VERSION 5.7 ;
BUSBITCHARS "[]" ;
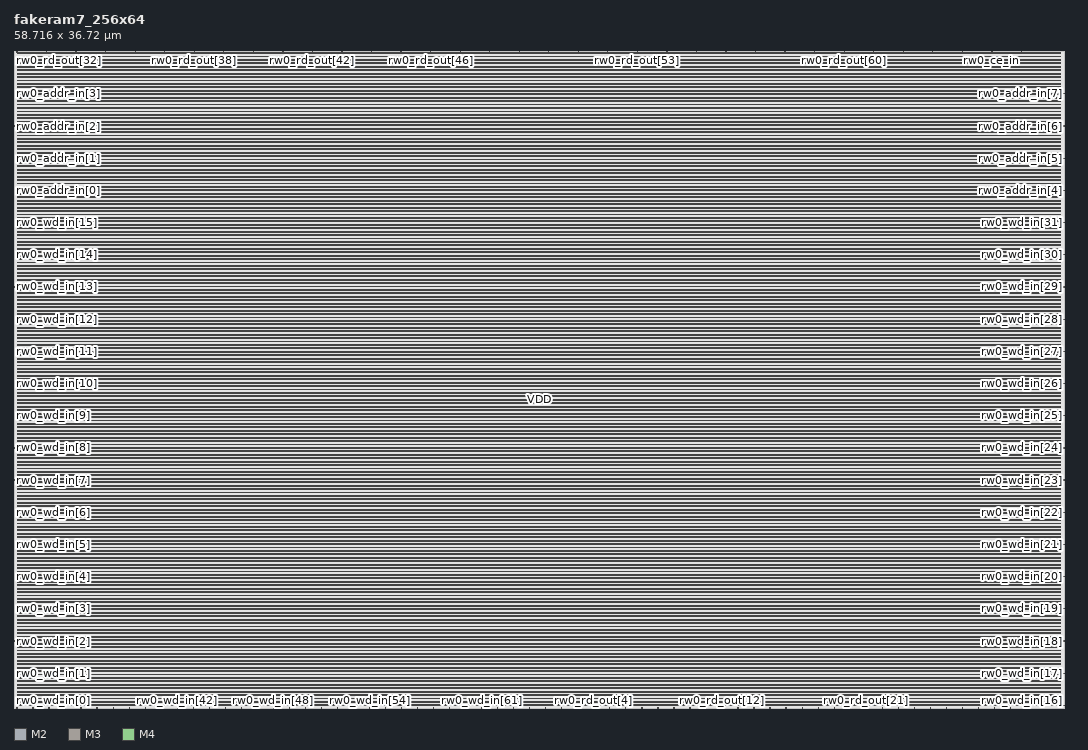
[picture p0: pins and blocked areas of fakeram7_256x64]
MACRO fakeram7_256x64
  FOREIGN fakeram7_256x64 0 0 ;
  SYMMETRY X Y R90 ;
  SIZE 58.716 BY 36.720 ;
  CLASS BLOCK ;
  PIN rw0_wd_in[0]
    DIRECTION INPUT ;
    USE SIGNAL ;
    SHAPE ABUTMENT ;
    PORT
      LAYER M2 ;
      RECT 0.000 0.138 0.036 0.150 ;
    END
  END rw0_wd_in[0]
  PIN rw0_wd_in[1]
    DIRECTION INPUT ;
    USE SIGNAL ;
    SHAPE ABUTMENT ;
    PORT
      LAYER M2 ;
      RECT 0.000 1.938 0.036 1.950 ;
    END
  END rw0_wd_in[1]
  PIN rw0_wd_in[2]
    DIRECTION INPUT ;
    USE SIGNAL ;
    SHAPE ABUTMENT ;
    PORT
      LAYER M2 ;
      RECT 0.000 3.738 0.036 3.750 ;
    END
  END rw0_wd_in[2]
  PIN rw0_wd_in[3]
    DIRECTION INPUT ;
    USE SIGNAL ;
    SHAPE ABUTMENT ;
    PORT
      LAYER M2 ;
      RECT 0.000 5.538 0.036 5.550 ;
    END
  END rw0_wd_in[3]
  PIN rw0_wd_in[4]
    DIRECTION INPUT ;
    USE SIGNAL ;
    SHAPE ABUTMENT ;
    PORT
      LAYER M2 ;
      RECT 0.000 7.338 0.036 7.350 ;
    END
  END rw0_wd_in[4]
  PIN rw0_wd_in[5]
    DIRECTION INPUT ;
    USE SIGNAL ;
    SHAPE ABUTMENT ;
    PORT
      LAYER M2 ;
      RECT 0.000 9.138 0.036 9.150 ;
    END
  END rw0_wd_in[5]
  PIN rw0_wd_in[6]
    DIRECTION INPUT ;
    USE SIGNAL ;
    SHAPE ABUTMENT ;
    PORT
      LAYER M2 ;
      RECT 0.000 10.938 0.036 10.950 ;
    END
  END rw0_wd_in[6]
  PIN rw0_wd_in[7]
    DIRECTION INPUT ;
    USE SIGNAL ;
    SHAPE ABUTMENT ;
    PORT
      LAYER M2 ;
      RECT 0.000 12.738 0.036 12.750 ;
    END
  END rw0_wd_in[7]
  PIN rw0_wd_in[8]
    DIRECTION INPUT ;
    USE SIGNAL ;
    SHAPE ABUTMENT ;
    PORT
      LAYER M2 ;
      RECT 0.000 14.538 0.036 14.550 ;
    END
  END rw0_wd_in[8]
  PIN rw0_wd_in[9]
    DIRECTION INPUT ;
    USE SIGNAL ;
    SHAPE ABUTMENT ;
    PORT
      LAYER M2 ;
      RECT 0.000 16.338 0.036 16.350 ;
    END
  END rw0_wd_in[9]
  PIN rw0_wd_in[10]
    DIRECTION INPUT ;
    USE SIGNAL ;
    SHAPE ABUTMENT ;
    PORT
      LAYER M2 ;
      RECT 0.000 18.138 0.036 18.150 ;
    END
  END rw0_wd_in[10]
  PIN rw0_wd_in[11]
    DIRECTION INPUT ;
    USE SIGNAL ;
    SHAPE ABUTMENT ;
    PORT
      LAYER M2 ;
      RECT 0.000 19.938 0.036 19.950 ;
    END
  END rw0_wd_in[11]
  PIN rw0_wd_in[12]
    DIRECTION INPUT ;
    USE SIGNAL ;
    SHAPE ABUTMENT ;
    PORT
      LAYER M2 ;
      RECT 0.000 21.738 0.036 21.750 ;
    END
  END rw0_wd_in[12]
  PIN rw0_wd_in[13]
    DIRECTION INPUT ;
    USE SIGNAL ;
    SHAPE ABUTMENT ;
    PORT
      LAYER M2 ;
      RECT 0.000 23.538 0.036 23.550 ;
    END
  END rw0_wd_in[13]
  PIN rw0_wd_in[14]
    DIRECTION INPUT ;
    USE SIGNAL ;
    SHAPE ABUTMENT ;
    PORT
      LAYER M2 ;
      RECT 0.000 25.338 0.036 25.350 ;
    END
  END rw0_wd_in[14]
  PIN rw0_wd_in[15]
    DIRECTION INPUT ;
    USE SIGNAL ;
    SHAPE ABUTMENT ;
    PORT
      LAYER M2 ;
      RECT 0.000 27.138 0.036 27.150 ;
    END
  END rw0_wd_in[15]
  PIN rw0_wd_in[16]
    DIRECTION INPUT ;
    USE SIGNAL ;
    SHAPE ABUTMENT ;
    PORT
      LAYER M2 ;
      RECT 58.680 0.138 58.716 0.150 ;
    END
  END rw0_wd_in[16]
  PIN rw0_wd_in[17]
    DIRECTION INPUT ;
    USE SIGNAL ;
    SHAPE ABUTMENT ;
    PORT
      LAYER M2 ;
      RECT 58.680 1.938 58.716 1.950 ;
    END
  END rw0_wd_in[17]
  PIN rw0_wd_in[18]
    DIRECTION INPUT ;
    USE SIGNAL ;
    SHAPE ABUTMENT ;
    PORT
      LAYER M2 ;
      RECT 58.680 3.738 58.716 3.750 ;
    END
  END rw0_wd_in[18]
  PIN rw0_wd_in[19]
    DIRECTION INPUT ;
    USE SIGNAL ;
    SHAPE ABUTMENT ;
    PORT
      LAYER M2 ;
      RECT 58.680 5.538 58.716 5.550 ;
    END
  END rw0_wd_in[19]
  PIN rw0_wd_in[20]
    DIRECTION INPUT ;
    USE SIGNAL ;
    SHAPE ABUTMENT ;
    PORT
      LAYER M2 ;
      RECT 58.680 7.338 58.716 7.350 ;
    END
  END rw0_wd_in[20]
  PIN rw0_wd_in[21]
    DIRECTION INPUT ;
    USE SIGNAL ;
    SHAPE ABUTMENT ;
    PORT
      LAYER M2 ;
      RECT 58.680 9.138 58.716 9.150 ;
    END
  END rw0_wd_in[21]
  PIN rw0_wd_in[22]
    DIRECTION INPUT ;
    USE SIGNAL ;
    SHAPE ABUTMENT ;
    PORT
      LAYER M2 ;
      RECT 58.680 10.938 58.716 10.950 ;
    END
  END rw0_wd_in[22]
  PIN rw0_wd_in[23]
    DIRECTION INPUT ;
    USE SIGNAL ;
    SHAPE ABUTMENT ;
    PORT
      LAYER M2 ;
      RECT 58.680 12.738 58.716 12.750 ;
    END
  END rw0_wd_in[23]
  PIN rw0_wd_in[24]
    DIRECTION INPUT ;
    USE SIGNAL ;
    SHAPE ABUTMENT ;
    PORT
      LAYER M2 ;
      RECT 58.680 14.538 58.716 14.550 ;
    END
  END rw0_wd_in[24]
  PIN rw0_wd_in[25]
    DIRECTION INPUT ;
    USE SIGNAL ;
    SHAPE ABUTMENT ;
    PORT
      LAYER M2 ;
      RECT 58.680 16.338 58.716 16.350 ;
    END
  END rw0_wd_in[25]
  PIN rw0_wd_in[26]
    DIRECTION INPUT ;
    USE SIGNAL ;
    SHAPE ABUTMENT ;
    PORT
      LAYER M2 ;
      RECT 58.680 18.138 58.716 18.150 ;
    END
  END rw0_wd_in[26]
  PIN rw0_wd_in[27]
    DIRECTION INPUT ;
    USE SIGNAL ;
    SHAPE ABUTMENT ;
    PORT
      LAYER M2 ;
      RECT 58.680 19.938 58.716 19.950 ;
    END
  END rw0_wd_in[27]
  PIN rw0_wd_in[28]
    DIRECTION INPUT ;
    USE SIGNAL ;
    SHAPE ABUTMENT ;
    PORT
      LAYER M2 ;
      RECT 58.680 21.738 58.716 21.750 ;
    END
  END rw0_wd_in[28]
  PIN rw0_wd_in[29]
    DIRECTION INPUT ;
    USE SIGNAL ;
    SHAPE ABUTMENT ;
    PORT
      LAYER M2 ;
      RECT 58.680 23.538 58.716 23.550 ;
    END
  END rw0_wd_in[29]
  PIN rw0_wd_in[30]
    DIRECTION INPUT ;
    USE SIGNAL ;
    SHAPE ABUTMENT ;
    PORT
      LAYER M2 ;
      RECT 58.680 25.338 58.716 25.350 ;
    END
  END rw0_wd_in[30]
  PIN rw0_wd_in[31]
    DIRECTION INPUT ;
    USE SIGNAL ;
    SHAPE ABUTMENT ;
    PORT
      LAYER M2 ;
      RECT 58.680 27.138 58.716 27.150 ;
    END
  END rw0_wd_in[31]
  PIN rw0_wd_in[32]
    DIRECTION INPUT ;
    USE SIGNAL ;
    SHAPE ABUTMENT ;
    PORT
      LAYER M3 ;
      RECT 0.161 0.000 0.175 0.042 ;
    END
  END rw0_wd_in[32]
  PIN rw0_wd_in[33]
    DIRECTION INPUT ;
    USE SIGNAL ;
    SHAPE ABUTMENT ;
    PORT
      LAYER M3 ;
      RECT 1.057 0.000 1.071 0.042 ;
    END
  END rw0_wd_in[33]
  PIN rw0_wd_in[34]
    DIRECTION INPUT ;
    USE SIGNAL ;
    SHAPE ABUTMENT ;
    PORT
      LAYER M3 ;
      RECT 1.953 0.000 1.967 0.042 ;
    END
  END rw0_wd_in[34]
  PIN rw0_wd_in[35]
    DIRECTION INPUT ;
    USE SIGNAL ;
    SHAPE ABUTMENT ;
    PORT
      LAYER M3 ;
      RECT 2.849 0.000 2.863 0.042 ;
    END
  END rw0_wd_in[35]
  PIN rw0_wd_in[36]
    DIRECTION INPUT ;
    USE SIGNAL ;
    SHAPE ABUTMENT ;
    PORT
      LAYER M3 ;
      RECT 3.745 0.000 3.759 0.042 ;
    END
  END rw0_wd_in[36]
  PIN rw0_wd_in[37]
    DIRECTION INPUT ;
    USE SIGNAL ;
    SHAPE ABUTMENT ;
    PORT
      LAYER M3 ;
      RECT 4.641 0.000 4.655 0.042 ;
    END
  END rw0_wd_in[37]
  PIN rw0_wd_in[38]
    DIRECTION INPUT ;
    USE SIGNAL ;
    SHAPE ABUTMENT ;
    PORT
      LAYER M3 ;
      RECT 5.537 0.000 5.551 0.042 ;
    END
  END rw0_wd_in[38]
  PIN rw0_wd_in[39]
    DIRECTION INPUT ;
    USE SIGNAL ;
    SHAPE ABUTMENT ;
    PORT
      LAYER M3 ;
      RECT 6.433 0.000 6.447 0.042 ;
    END
  END rw0_wd_in[39]
  PIN rw0_wd_in[40]
    DIRECTION INPUT ;
    USE SIGNAL ;
    SHAPE ABUTMENT ;
    PORT
      LAYER M3 ;
      RECT 7.329 0.000 7.343 0.042 ;
    END
  END rw0_wd_in[40]
  PIN rw0_wd_in[41]
    DIRECTION INPUT ;
    USE SIGNAL ;
    SHAPE ABUTMENT ;
    PORT
      LAYER M3 ;
      RECT 8.225 0.000 8.239 0.042 ;
    END
  END rw0_wd_in[41]
  PIN rw0_wd_in[42]
    DIRECTION INPUT ;
    USE SIGNAL ;
    SHAPE ABUTMENT ;
    PORT
      LAYER M3 ;
      RECT 9.121 0.000 9.135 0.042 ;
    END
  END rw0_wd_in[42]
  PIN rw0_wd_in[43]
    DIRECTION INPUT ;
    USE SIGNAL ;
    SHAPE ABUTMENT ;
    PORT
      LAYER M3 ;
      RECT 10.017 0.000 10.031 0.042 ;
    END
  END rw0_wd_in[43]
  PIN rw0_wd_in[44]
    DIRECTION INPUT ;
    USE SIGNAL ;
    SHAPE ABUTMENT ;
    PORT
      LAYER M3 ;
      RECT 10.913 0.000 10.927 0.042 ;
    END
  END rw0_wd_in[44]
  PIN rw0_wd_in[45]
    DIRECTION INPUT ;
    USE SIGNAL ;
    SHAPE ABUTMENT ;
    PORT
      LAYER M3 ;
      RECT 11.809 0.000 11.823 0.042 ;
    END
  END rw0_wd_in[45]
  PIN rw0_wd_in[46]
    DIRECTION INPUT ;
    USE SIGNAL ;
    SHAPE ABUTMENT ;
    PORT
      LAYER M3 ;
      RECT 12.705 0.000 12.719 0.042 ;
    END
  END rw0_wd_in[46]
  PIN rw0_wd_in[47]
    DIRECTION INPUT ;
    USE SIGNAL ;
    SHAPE ABUTMENT ;
    PORT
      LAYER M3 ;
      RECT 13.601 0.000 13.615 0.042 ;
    END
  END rw0_wd_in[47]
  PIN rw0_wd_in[48]
    DIRECTION INPUT ;
    USE SIGNAL ;
    SHAPE ABUTMENT ;
    PORT
      LAYER M3 ;
      RECT 14.497 0.000 14.511 0.042 ;
    END
  END rw0_wd_in[48]
  PIN rw0_wd_in[49]
    DIRECTION INPUT ;
    USE SIGNAL ;
    SHAPE ABUTMENT ;
    PORT
      LAYER M3 ;
      RECT 15.393 0.000 15.407 0.042 ;
    END
  END rw0_wd_in[49]
  PIN rw0_wd_in[50]
    DIRECTION INPUT ;
    USE SIGNAL ;
    SHAPE ABUTMENT ;
    PORT
      LAYER M3 ;
      RECT 16.289 0.000 16.303 0.042 ;
    END
  END rw0_wd_in[50]
  PIN rw0_wd_in[51]
    DIRECTION INPUT ;
    USE SIGNAL ;
    SHAPE ABUTMENT ;
    PORT
      LAYER M3 ;
      RECT 17.185 0.000 17.199 0.042 ;
    END
  END rw0_wd_in[51]
  PIN rw0_wd_in[52]
    DIRECTION INPUT ;
    USE SIGNAL ;
    SHAPE ABUTMENT ;
    PORT
      LAYER M3 ;
      RECT 18.081 0.000 18.095 0.042 ;
    END
  END rw0_wd_in[52]
  PIN rw0_wd_in[53]
    DIRECTION INPUT ;
    USE SIGNAL ;
    SHAPE ABUTMENT ;
    PORT
      LAYER M3 ;
      RECT 18.977 0.000 18.991 0.042 ;
    END
  END rw0_wd_in[53]
  PIN rw0_wd_in[54]
    DIRECTION INPUT ;
    USE SIGNAL ;
    SHAPE ABUTMENT ;
    PORT
      LAYER M3 ;
      RECT 19.873 0.000 19.887 0.042 ;
    END
  END rw0_wd_in[54]
  PIN rw0_wd_in[55]
    DIRECTION INPUT ;
    USE SIGNAL ;
    SHAPE ABUTMENT ;
    PORT
      LAYER M3 ;
      RECT 20.769 0.000 20.783 0.042 ;
    END
  END rw0_wd_in[55]
  PIN rw0_wd_in[56]
    DIRECTION INPUT ;
    USE SIGNAL ;
    SHAPE ABUTMENT ;
    PORT
      LAYER M3 ;
      RECT 21.665 0.000 21.679 0.042 ;
    END
  END rw0_wd_in[56]
  PIN rw0_wd_in[57]
    DIRECTION INPUT ;
    USE SIGNAL ;
    SHAPE ABUTMENT ;
    PORT
      LAYER M3 ;
      RECT 22.561 0.000 22.575 0.042 ;
    END
  END rw0_wd_in[57]
  PIN rw0_wd_in[58]
    DIRECTION INPUT ;
    USE SIGNAL ;
    SHAPE ABUTMENT ;
    PORT
      LAYER M3 ;
      RECT 23.457 0.000 23.471 0.042 ;
    END
  END rw0_wd_in[58]
  PIN rw0_wd_in[59]
    DIRECTION INPUT ;
    USE SIGNAL ;
    SHAPE ABUTMENT ;
    PORT
      LAYER M3 ;
      RECT 24.353 0.000 24.367 0.042 ;
    END
  END rw0_wd_in[59]
  PIN rw0_wd_in[60]
    DIRECTION INPUT ;
    USE SIGNAL ;
    SHAPE ABUTMENT ;
    PORT
      LAYER M3 ;
      RECT 25.249 0.000 25.263 0.042 ;
    END
  END rw0_wd_in[60]
  PIN rw0_wd_in[61]
    DIRECTION INPUT ;
    USE SIGNAL ;
    SHAPE ABUTMENT ;
    PORT
      LAYER M3 ;
      RECT 26.145 0.000 26.159 0.042 ;
    END
  END rw0_wd_in[61]
  PIN rw0_wd_in[62]
    DIRECTION INPUT ;
    USE SIGNAL ;
    SHAPE ABUTMENT ;
    PORT
      LAYER M3 ;
      RECT 27.041 0.000 27.055 0.042 ;
    END
  END rw0_wd_in[62]
  PIN rw0_wd_in[63]
    DIRECTION INPUT ;
    USE SIGNAL ;
    SHAPE ABUTMENT ;
    PORT
      LAYER M3 ;
      RECT 27.937 0.000 27.951 0.042 ;
    END
  END rw0_wd_in[63]
  PIN rw0_rd_out[0]
    DIRECTION OUTPUT ;
    USE SIGNAL ;
    SHAPE ABUTMENT ;
    PORT
      LAYER M3 ;
      RECT 28.833 0.000 28.847 0.042 ;
    END
  END rw0_rd_out[0]
  PIN rw0_rd_out[1]
    DIRECTION OUTPUT ;
    USE SIGNAL ;
    SHAPE ABUTMENT ;
    PORT
      LAYER M3 ;
      RECT 29.729 0.000 29.743 0.042 ;
    END
  END rw0_rd_out[1]
  PIN rw0_rd_out[2]
    DIRECTION OUTPUT ;
    USE SIGNAL ;
    SHAPE ABUTMENT ;
    PORT
      LAYER M3 ;
      RECT 30.625 0.000 30.639 0.042 ;
    END
  END rw0_rd_out[2]
  PIN rw0_rd_out[3]
    DIRECTION OUTPUT ;
    USE SIGNAL ;
    SHAPE ABUTMENT ;
    PORT
      LAYER M3 ;
      RECT 31.521 0.000 31.535 0.042 ;
    END
  END rw0_rd_out[3]
  PIN rw0_rd_out[4]
    DIRECTION OUTPUT ;
    USE SIGNAL ;
    SHAPE ABUTMENT ;
    PORT
      LAYER M3 ;
      RECT 32.417 0.000 32.431 0.042 ;
    END
  END rw0_rd_out[4]
  PIN rw0_rd_out[5]
    DIRECTION OUTPUT ;
    USE SIGNAL ;
    SHAPE ABUTMENT ;
    PORT
      LAYER M3 ;
      RECT 33.313 0.000 33.327 0.042 ;
    END
  END rw0_rd_out[5]
  PIN rw0_rd_out[6]
    DIRECTION OUTPUT ;
    USE SIGNAL ;
    SHAPE ABUTMENT ;
    PORT
      LAYER M3 ;
      RECT 34.209 0.000 34.223 0.042 ;
    END
  END rw0_rd_out[6]
  PIN rw0_rd_out[7]
    DIRECTION OUTPUT ;
    USE SIGNAL ;
    SHAPE ABUTMENT ;
    PORT
      LAYER M3 ;
      RECT 35.105 0.000 35.119 0.042 ;
    END
  END rw0_rd_out[7]
  PIN rw0_rd_out[8]
    DIRECTION OUTPUT ;
    USE SIGNAL ;
    SHAPE ABUTMENT ;
    PORT
      LAYER M3 ;
      RECT 36.001 0.000 36.015 0.042 ;
    END
  END rw0_rd_out[8]
  PIN rw0_rd_out[9]
    DIRECTION OUTPUT ;
    USE SIGNAL ;
    SHAPE ABUTMENT ;
    PORT
      LAYER M3 ;
      RECT 36.897 0.000 36.911 0.042 ;
    END
  END rw0_rd_out[9]
  PIN rw0_rd_out[10]
    DIRECTION OUTPUT ;
    USE SIGNAL ;
    SHAPE ABUTMENT ;
    PORT
      LAYER M3 ;
      RECT 37.793 0.000 37.807 0.042 ;
    END
  END rw0_rd_out[10]
  PIN rw0_rd_out[11]
    DIRECTION OUTPUT ;
    USE SIGNAL ;
    SHAPE ABUTMENT ;
    PORT
      LAYER M3 ;
      RECT 38.689 0.000 38.703 0.042 ;
    END
  END rw0_rd_out[11]
  PIN rw0_rd_out[12]
    DIRECTION OUTPUT ;
    USE SIGNAL ;
    SHAPE ABUTMENT ;
    PORT
      LAYER M3 ;
      RECT 39.585 0.000 39.599 0.042 ;
    END
  END rw0_rd_out[12]
  PIN rw0_rd_out[13]
    DIRECTION OUTPUT ;
    USE SIGNAL ;
    SHAPE ABUTMENT ;
    PORT
      LAYER M3 ;
      RECT 40.481 0.000 40.495 0.042 ;
    END
  END rw0_rd_out[13]
  PIN rw0_rd_out[14]
    DIRECTION OUTPUT ;
    USE SIGNAL ;
    SHAPE ABUTMENT ;
    PORT
      LAYER M3 ;
      RECT 41.377 0.000 41.391 0.042 ;
    END
  END rw0_rd_out[14]
  PIN rw0_rd_out[15]
    DIRECTION OUTPUT ;
    USE SIGNAL ;
    SHAPE ABUTMENT ;
    PORT
      LAYER M3 ;
      RECT 42.273 0.000 42.287 0.042 ;
    END
  END rw0_rd_out[15]
  PIN rw0_rd_out[16]
    DIRECTION OUTPUT ;
    USE SIGNAL ;
    SHAPE ABUTMENT ;
    PORT
      LAYER M3 ;
      RECT 43.169 0.000 43.183 0.042 ;
    END
  END rw0_rd_out[16]
  PIN rw0_rd_out[17]
    DIRECTION OUTPUT ;
    USE SIGNAL ;
    SHAPE ABUTMENT ;
    PORT
      LAYER M3 ;
      RECT 44.065 0.000 44.079 0.042 ;
    END
  END rw0_rd_out[17]
  PIN rw0_rd_out[18]
    DIRECTION OUTPUT ;
    USE SIGNAL ;
    SHAPE ABUTMENT ;
    PORT
      LAYER M3 ;
      RECT 44.961 0.000 44.975 0.042 ;
    END
  END rw0_rd_out[18]
  PIN rw0_rd_out[19]
    DIRECTION OUTPUT ;
    USE SIGNAL ;
    SHAPE ABUTMENT ;
    PORT
      LAYER M3 ;
      RECT 45.857 0.000 45.871 0.042 ;
    END
  END rw0_rd_out[19]
  PIN rw0_rd_out[20]
    DIRECTION OUTPUT ;
    USE SIGNAL ;
    SHAPE ABUTMENT ;
    PORT
      LAYER M3 ;
      RECT 46.753 0.000 46.767 0.042 ;
    END
  END rw0_rd_out[20]
  PIN rw0_rd_out[21]
    DIRECTION OUTPUT ;
    USE SIGNAL ;
    SHAPE ABUTMENT ;
    PORT
      LAYER M3 ;
      RECT 47.649 0.000 47.663 0.042 ;
    END
  END rw0_rd_out[21]
  PIN rw0_rd_out[22]
    DIRECTION OUTPUT ;
    USE SIGNAL ;
    SHAPE ABUTMENT ;
    PORT
      LAYER M3 ;
      RECT 48.545 0.000 48.559 0.042 ;
    END
  END rw0_rd_out[22]
  PIN rw0_rd_out[23]
    DIRECTION OUTPUT ;
    USE SIGNAL ;
    SHAPE ABUTMENT ;
    PORT
      LAYER M3 ;
      RECT 49.441 0.000 49.455 0.042 ;
    END
  END rw0_rd_out[23]
  PIN rw0_rd_out[24]
    DIRECTION OUTPUT ;
    USE SIGNAL ;
    SHAPE ABUTMENT ;
    PORT
      LAYER M3 ;
      RECT 50.337 0.000 50.351 0.042 ;
    END
  END rw0_rd_out[24]
  PIN rw0_rd_out[25]
    DIRECTION OUTPUT ;
    USE SIGNAL ;
    SHAPE ABUTMENT ;
    PORT
      LAYER M3 ;
      RECT 51.233 0.000 51.247 0.042 ;
    END
  END rw0_rd_out[25]
  PIN rw0_rd_out[26]
    DIRECTION OUTPUT ;
    USE SIGNAL ;
    SHAPE ABUTMENT ;
    PORT
      LAYER M3 ;
      RECT 52.129 0.000 52.143 0.042 ;
    END
  END rw0_rd_out[26]
  PIN rw0_rd_out[27]
    DIRECTION OUTPUT ;
    USE SIGNAL ;
    SHAPE ABUTMENT ;
    PORT
      LAYER M3 ;
      RECT 53.025 0.000 53.039 0.042 ;
    END
  END rw0_rd_out[27]
  PIN rw0_rd_out[28]
    DIRECTION OUTPUT ;
    USE SIGNAL ;
    SHAPE ABUTMENT ;
    PORT
      LAYER M3 ;
      RECT 53.921 0.000 53.935 0.042 ;
    END
  END rw0_rd_out[28]
  PIN rw0_rd_out[29]
    DIRECTION OUTPUT ;
    USE SIGNAL ;
    SHAPE ABUTMENT ;
    PORT
      LAYER M3 ;
      RECT 54.817 0.000 54.831 0.042 ;
    END
  END rw0_rd_out[29]
  PIN rw0_rd_out[30]
    DIRECTION OUTPUT ;
    USE SIGNAL ;
    SHAPE ABUTMENT ;
    PORT
      LAYER M3 ;
      RECT 55.713 0.000 55.727 0.042 ;
    END
  END rw0_rd_out[30]
  PIN rw0_rd_out[31]
    DIRECTION OUTPUT ;
    USE SIGNAL ;
    SHAPE ABUTMENT ;
    PORT
      LAYER M3 ;
      RECT 56.609 0.000 56.623 0.042 ;
    END
  END rw0_rd_out[31]
  PIN rw0_rd_out[32]
    DIRECTION OUTPUT ;
    USE SIGNAL ;
    SHAPE ABUTMENT ;
    PORT
      LAYER M3 ;
      RECT 0.161 36.678 0.175 36.720 ;
    END
  END rw0_rd_out[32]
  PIN rw0_rd_out[33]
    DIRECTION OUTPUT ;
    USE SIGNAL ;
    SHAPE ABUTMENT ;
    PORT
      LAYER M3 ;
      RECT 1.813 36.678 1.827 36.720 ;
    END
  END rw0_rd_out[33]
  PIN rw0_rd_out[34]
    DIRECTION OUTPUT ;
    USE SIGNAL ;
    SHAPE ABUTMENT ;
    PORT
      LAYER M3 ;
      RECT 3.465 36.678 3.479 36.720 ;
    END
  END rw0_rd_out[34]
  PIN rw0_rd_out[35]
    DIRECTION OUTPUT ;
    USE SIGNAL ;
    SHAPE ABUTMENT ;
    PORT
      LAYER M3 ;
      RECT 5.117 36.678 5.131 36.720 ;
    END
  END rw0_rd_out[35]
  PIN rw0_rd_out[36]
    DIRECTION OUTPUT ;
    USE SIGNAL ;
    SHAPE ABUTMENT ;
    PORT
      LAYER M3 ;
      RECT 6.769 36.678 6.783 36.720 ;
    END
  END rw0_rd_out[36]
  PIN rw0_rd_out[37]
    DIRECTION OUTPUT ;
    USE SIGNAL ;
    SHAPE ABUTMENT ;
    PORT
      LAYER M3 ;
      RECT 8.421 36.678 8.435 36.720 ;
    END
  END rw0_rd_out[37]
  PIN rw0_rd_out[38]
    DIRECTION OUTPUT ;
    USE SIGNAL ;
    SHAPE ABUTMENT ;
    PORT
      LAYER M3 ;
      RECT 10.073 36.678 10.087 36.720 ;
    END
  END rw0_rd_out[38]
  PIN rw0_rd_out[39]
    DIRECTION OUTPUT ;
    USE SIGNAL ;
    SHAPE ABUTMENT ;
    PORT
      LAYER M3 ;
      RECT 11.725 36.678 11.739 36.720 ;
    END
  END rw0_rd_out[39]
  PIN rw0_rd_out[40]
    DIRECTION OUTPUT ;
    USE SIGNAL ;
    SHAPE ABUTMENT ;
    PORT
      LAYER M3 ;
      RECT 13.377 36.678 13.391 36.720 ;
    END
  END rw0_rd_out[40]
  PIN rw0_rd_out[41]
    DIRECTION OUTPUT ;
    USE SIGNAL ;
    SHAPE ABUTMENT ;
    PORT
      LAYER M3 ;
      RECT 15.029 36.678 15.043 36.720 ;
    END
  END rw0_rd_out[41]
  PIN rw0_rd_out[42]
    DIRECTION OUTPUT ;
    USE SIGNAL ;
    SHAPE ABUTMENT ;
    PORT
      LAYER M3 ;
      RECT 16.681 36.678 16.695 36.720 ;
    END
  END rw0_rd_out[42]
  PIN rw0_rd_out[43]
    DIRECTION OUTPUT ;
    USE SIGNAL ;
    SHAPE ABUTMENT ;
    PORT
      LAYER M3 ;
      RECT 18.333 36.678 18.347 36.720 ;
    END
  END rw0_rd_out[43]
  PIN rw0_rd_out[44]
    DIRECTION OUTPUT ;
    USE SIGNAL ;
    SHAPE ABUTMENT ;
    PORT
      LAYER M3 ;
      RECT 19.985 36.678 19.999 36.720 ;
    END
  END rw0_rd_out[44]
  PIN rw0_rd_out[45]
    DIRECTION OUTPUT ;
    USE SIGNAL ;
    SHAPE ABUTMENT ;
    PORT
      LAYER M3 ;
      RECT 21.637 36.678 21.651 36.720 ;
    END
  END rw0_rd_out[45]
  PIN rw0_rd_out[46]
    DIRECTION OUTPUT ;
    USE SIGNAL ;
    SHAPE ABUTMENT ;
    PORT
      LAYER M3 ;
      RECT 23.289 36.678 23.303 36.720 ;
    END
  END rw0_rd_out[46]
  PIN rw0_rd_out[47]
    DIRECTION OUTPUT ;
    USE SIGNAL ;
    SHAPE ABUTMENT ;
    PORT
      LAYER M3 ;
      RECT 24.941 36.678 24.955 36.720 ;
    END
  END rw0_rd_out[47]
  PIN rw0_rd_out[48]
    DIRECTION OUTPUT ;
    USE SIGNAL ;
    SHAPE ABUTMENT ;
    PORT
      LAYER M3 ;
      RECT 26.593 36.678 26.607 36.720 ;
    END
  END rw0_rd_out[48]
  PIN rw0_rd_out[49]
    DIRECTION OUTPUT ;
    USE SIGNAL ;
    SHAPE ABUTMENT ;
    PORT
      LAYER M3 ;
      RECT 28.245 36.678 28.259 36.720 ;
    END
  END rw0_rd_out[49]
  PIN rw0_rd_out[50]
    DIRECTION OUTPUT ;
    USE SIGNAL ;
    SHAPE ABUTMENT ;
    PORT
      LAYER M3 ;
      RECT 29.897 36.678 29.911 36.720 ;
    END
  END rw0_rd_out[50]
  PIN rw0_rd_out[51]
    DIRECTION OUTPUT ;
    USE SIGNAL ;
    SHAPE ABUTMENT ;
    PORT
      LAYER M3 ;
      RECT 31.549 36.678 31.563 36.720 ;
    END
  END rw0_rd_out[51]
  PIN rw0_rd_out[52]
    DIRECTION OUTPUT ;
    USE SIGNAL ;
    SHAPE ABUTMENT ;
    PORT
      LAYER M3 ;
      RECT 33.201 36.678 33.215 36.720 ;
    END
  END rw0_rd_out[52]
  PIN rw0_rd_out[53]
    DIRECTION OUTPUT ;
    USE SIGNAL ;
    SHAPE ABUTMENT ;
    PORT
      LAYER M3 ;
      RECT 34.853 36.678 34.867 36.720 ;
    END
  END rw0_rd_out[53]
  PIN rw0_rd_out[54]
    DIRECTION OUTPUT ;
    USE SIGNAL ;
    SHAPE ABUTMENT ;
    PORT
      LAYER M3 ;
      RECT 36.505 36.678 36.519 36.720 ;
    END
  END rw0_rd_out[54]
  PIN rw0_rd_out[55]
    DIRECTION OUTPUT ;
    USE SIGNAL ;
    SHAPE ABUTMENT ;
    PORT
      LAYER M3 ;
      RECT 38.157 36.678 38.171 36.720 ;
    END
  END rw0_rd_out[55]
  PIN rw0_rd_out[56]
    DIRECTION OUTPUT ;
    USE SIGNAL ;
    SHAPE ABUTMENT ;
    PORT
      LAYER M3 ;
      RECT 39.809 36.678 39.823 36.720 ;
    END
  END rw0_rd_out[56]
  PIN rw0_rd_out[57]
    DIRECTION OUTPUT ;
    USE SIGNAL ;
    SHAPE ABUTMENT ;
    PORT
      LAYER M3 ;
      RECT 41.461 36.678 41.475 36.720 ;
    END
  END rw0_rd_out[57]
  PIN rw0_rd_out[58]
    DIRECTION OUTPUT ;
    USE SIGNAL ;
    SHAPE ABUTMENT ;
    PORT
      LAYER M3 ;
      RECT 43.113 36.678 43.127 36.720 ;
    END
  END rw0_rd_out[58]
  PIN rw0_rd_out[59]
    DIRECTION OUTPUT ;
    USE SIGNAL ;
    SHAPE ABUTMENT ;
    PORT
      LAYER M3 ;
      RECT 44.765 36.678 44.779 36.720 ;
    END
  END rw0_rd_out[59]
  PIN rw0_rd_out[60]
    DIRECTION OUTPUT ;
    USE SIGNAL ;
    SHAPE ABUTMENT ;
    PORT
      LAYER M3 ;
      RECT 46.417 36.678 46.431 36.720 ;
    END
  END rw0_rd_out[60]
  PIN rw0_rd_out[61]
    DIRECTION OUTPUT ;
    USE SIGNAL ;
    SHAPE ABUTMENT ;
    PORT
      LAYER M3 ;
      RECT 48.069 36.678 48.083 36.720 ;
    END
  END rw0_rd_out[61]
  PIN rw0_rd_out[62]
    DIRECTION OUTPUT ;
    USE SIGNAL ;
    SHAPE ABUTMENT ;
    PORT
      LAYER M3 ;
      RECT 49.721 36.678 49.735 36.720 ;
    END
  END rw0_rd_out[62]
  PIN rw0_rd_out[63]
    DIRECTION OUTPUT ;
    USE SIGNAL ;
    SHAPE ABUTMENT ;
    PORT
      LAYER M3 ;
      RECT 51.373 36.678 51.387 36.720 ;
    END
  END rw0_rd_out[63]
  PIN rw0_addr_in[0]
    DIRECTION INPUT ;
    USE SIGNAL ;
    SHAPE ABUTMENT ;
    PORT
      LAYER M2 ;
      RECT 0.000 28.938 0.036 28.950 ;
    END
  END rw0_addr_in[0]
  PIN rw0_addr_in[1]
    DIRECTION INPUT ;
    USE SIGNAL ;
    SHAPE ABUTMENT ;
    PORT
      LAYER M2 ;
      RECT 0.000 30.738 0.036 30.750 ;
    END
  END rw0_addr_in[1]
  PIN rw0_addr_in[2]
    DIRECTION INPUT ;
    USE SIGNAL ;
    SHAPE ABUTMENT ;
    PORT
      LAYER M2 ;
      RECT 0.000 32.538 0.036 32.550 ;
    END
  END rw0_addr_in[2]
  PIN rw0_addr_in[3]
    DIRECTION INPUT ;
    USE SIGNAL ;
    SHAPE ABUTMENT ;
    PORT
      LAYER M2 ;
      RECT 0.000 34.338 0.036 34.350 ;
    END
  END rw0_addr_in[3]
  PIN rw0_addr_in[4]
    DIRECTION INPUT ;
    USE SIGNAL ;
    SHAPE ABUTMENT ;
    PORT
      LAYER M2 ;
      RECT 58.680 28.938 58.716 28.950 ;
    END
  END rw0_addr_in[4]
  PIN rw0_addr_in[5]
    DIRECTION INPUT ;
    USE SIGNAL ;
    SHAPE ABUTMENT ;
    PORT
      LAYER M2 ;
      RECT 58.680 30.738 58.716 30.750 ;
    END
  END rw0_addr_in[5]
  PIN rw0_addr_in[6]
    DIRECTION INPUT ;
    USE SIGNAL ;
    SHAPE ABUTMENT ;
    PORT
      LAYER M2 ;
      RECT 58.680 32.538 58.716 32.550 ;
    END
  END rw0_addr_in[6]
  PIN rw0_addr_in[7]
    DIRECTION INPUT ;
    USE SIGNAL ;
    SHAPE ABUTMENT ;
    PORT
      LAYER M2 ;
      RECT 58.680 34.338 58.716 34.350 ;
    END
  END rw0_addr_in[7]
  PIN rw0_we_in
    DIRECTION INPUT ;
    USE SIGNAL ;
    SHAPE ABUTMENT ;
    PORT
      LAYER M3 ;
      RECT 53.025 36.678 53.039 36.720 ;
    END
  END rw0_we_in
  PIN rw0_ce_in
    DIRECTION INPUT ;
    USE SIGNAL ;
    SHAPE ABUTMENT ;
    PORT
      LAYER M3 ;
      RECT 54.677 36.678 54.691 36.720 ;
    END
  END rw0_ce_in
  PIN rw0_clk
    DIRECTION INPUT ;
    USE SIGNAL ;
    SHAPE ABUTMENT ;
    PORT
      LAYER M3 ;
      RECT 56.329 36.678 56.343 36.720 ;
    END
  END rw0_clk
  PIN VSS
    DIRECTION INOUT ;
    USE GROUND ;
    PORT
      LAYER M4 ;
      RECT 0.168 0.120 58.548 0.168 ;
      RECT 0.168 0.504 58.548 0.552 ;
      RECT 0.168 0.888 58.548 0.936 ;
      RECT 0.168 1.272 58.548 1.320 ;
      RECT 0.168 1.656 58.548 1.704 ;
      RECT 0.168 2.040 58.548 2.088 ;
      RECT 0.168 2.424 58.548 2.472 ;
      RECT 0.168 2.808 58.548 2.856 ;
      RECT 0.168 3.192 58.548 3.240 ;
      RECT 0.168 3.576 58.548 3.624 ;
      RECT 0.168 3.960 58.548 4.008 ;
      RECT 0.168 4.344 58.548 4.392 ;
      RECT 0.168 4.728 58.548 4.776 ;
      RECT 0.168 5.112 58.548 5.160 ;
      RECT 0.168 5.496 58.548 5.544 ;
      RECT 0.168 5.880 58.548 5.928 ;
      RECT 0.168 6.264 58.548 6.312 ;
      RECT 0.168 6.648 58.548 6.696 ;
      RECT 0.168 7.032 58.548 7.080 ;
      RECT 0.168 7.416 58.548 7.464 ;
      RECT 0.168 7.800 58.548 7.848 ;
      RECT 0.168 8.184 58.548 8.232 ;
      RECT 0.168 8.568 58.548 8.616 ;
      RECT 0.168 8.952 58.548 9.000 ;
      RECT 0.168 9.336 58.548 9.384 ;
      RECT 0.168 9.720 58.548 9.768 ;
      RECT 0.168 10.104 58.548 10.152 ;
      RECT 0.168 10.488 58.548 10.536 ;
      RECT 0.168 10.872 58.548 10.920 ;
      RECT 0.168 11.256 58.548 11.304 ;
      RECT 0.168 11.640 58.548 11.688 ;
      RECT 0.168 12.024 58.548 12.072 ;
      RECT 0.168 12.408 58.548 12.456 ;
      RECT 0.168 12.792 58.548 12.840 ;
      RECT 0.168 13.176 58.548 13.224 ;
      RECT 0.168 13.560 58.548 13.608 ;
      RECT 0.168 13.944 58.548 13.992 ;
      RECT 0.168 14.328 58.548 14.376 ;
      RECT 0.168 14.712 58.548 14.760 ;
      RECT 0.168 15.096 58.548 15.144 ;
      RECT 0.168 15.480 58.548 15.528 ;
      RECT 0.168 15.864 58.548 15.912 ;
      RECT 0.168 16.248 58.548 16.296 ;
      RECT 0.168 16.632 58.548 16.680 ;
      RECT 0.168 17.016 58.548 17.064 ;
      RECT 0.168 17.400 58.548 17.448 ;
      RECT 0.168 17.784 58.548 17.832 ;
      RECT 0.168 18.168 58.548 18.216 ;
      RECT 0.168 18.552 58.548 18.600 ;
      RECT 0.168 18.936 58.548 18.984 ;
      RECT 0.168 19.320 58.548 19.368 ;
      RECT 0.168 19.704 58.548 19.752 ;
      RECT 0.168 20.088 58.548 20.136 ;
      RECT 0.168 20.472 58.548 20.520 ;
      RECT 0.168 20.856 58.548 20.904 ;
      RECT 0.168 21.240 58.548 21.288 ;
      RECT 0.168 21.624 58.548 21.672 ;
      RECT 0.168 22.008 58.548 22.056 ;
      RECT 0.168 22.392 58.548 22.440 ;
      RECT 0.168 22.776 58.548 22.824 ;
      RECT 0.168 23.160 58.548 23.208 ;
      RECT 0.168 23.544 58.548 23.592 ;
      RECT 0.168 23.928 58.548 23.976 ;
      RECT 0.168 24.312 58.548 24.360 ;
      RECT 0.168 24.696 58.548 24.744 ;
      RECT 0.168 25.080 58.548 25.128 ;
      RECT 0.168 25.464 58.548 25.512 ;
      RECT 0.168 25.848 58.548 25.896 ;
      RECT 0.168 26.232 58.548 26.280 ;
      RECT 0.168 26.616 58.548 26.664 ;
      RECT 0.168 27.000 58.548 27.048 ;
      RECT 0.168 27.384 58.548 27.432 ;
      RECT 0.168 27.768 58.548 27.816 ;
      RECT 0.168 28.152 58.548 28.200 ;
      RECT 0.168 28.536 58.548 28.584 ;
      RECT 0.168 28.920 58.548 28.968 ;
      RECT 0.168 29.304 58.548 29.352 ;
      RECT 0.168 29.688 58.548 29.736 ;
      RECT 0.168 30.072 58.548 30.120 ;
      RECT 0.168 30.456 58.548 30.504 ;
      RECT 0.168 30.840 58.548 30.888 ;
      RECT 0.168 31.224 58.548 31.272 ;
      RECT 0.168 31.608 58.548 31.656 ;
      RECT 0.168 31.992 58.548 32.040 ;
      RECT 0.168 32.376 58.548 32.424 ;
      RECT 0.168 32.760 58.548 32.808 ;
      RECT 0.168 33.144 58.548 33.192 ;
      RECT 0.168 33.528 58.548 33.576 ;
      RECT 0.168 33.912 58.548 33.960 ;
      RECT 0.168 34.296 58.548 34.344 ;
      RECT 0.168 34.680 58.548 34.728 ;
      RECT 0.168 35.064 58.548 35.112 ;
      RECT 0.168 35.448 58.548 35.496 ;
      RECT 0.168 35.832 58.548 35.880 ;
      RECT 0.168 36.216 58.548 36.264 ;
      RECT 0.168 36.600 58.548 36.648 ;
    END
  END VSS
  PIN VDD
    DIRECTION INOUT ;
    USE POWER ;
    PORT
      LAYER M4 ;
      RECT 0.168 0.312 58.548 0.360 ;
      RECT 0.168 0.696 58.548 0.744 ;
      RECT 0.168 1.080 58.548 1.128 ;
      RECT 0.168 1.464 58.548 1.512 ;
      RECT 0.168 1.848 58.548 1.896 ;
      RECT 0.168 2.232 58.548 2.280 ;
      RECT 0.168 2.616 58.548 2.664 ;
      RECT 0.168 3.000 58.548 3.048 ;
      RECT 0.168 3.384 58.548 3.432 ;
      RECT 0.168 3.768 58.548 3.816 ;
      RECT 0.168 4.152 58.548 4.200 ;
      RECT 0.168 4.536 58.548 4.584 ;
      RECT 0.168 4.920 58.548 4.968 ;
      RECT 0.168 5.304 58.548 5.352 ;
      RECT 0.168 5.688 58.548 5.736 ;
      RECT 0.168 6.072 58.548 6.120 ;
      RECT 0.168 6.456 58.548 6.504 ;
      RECT 0.168 6.840 58.548 6.888 ;
      RECT 0.168 7.224 58.548 7.272 ;
      RECT 0.168 7.608 58.548 7.656 ;
      RECT 0.168 7.992 58.548 8.040 ;
      RECT 0.168 8.376 58.548 8.424 ;
      RECT 0.168 8.760 58.548 8.808 ;
      RECT 0.168 9.144 58.548 9.192 ;
      RECT 0.168 9.528 58.548 9.576 ;
      RECT 0.168 9.912 58.548 9.960 ;
      RECT 0.168 10.296 58.548 10.344 ;
      RECT 0.168 10.680 58.548 10.728 ;
      RECT 0.168 11.064 58.548 11.112 ;
      RECT 0.168 11.448 58.548 11.496 ;
      RECT 0.168 11.832 58.548 11.880 ;
      RECT 0.168 12.216 58.548 12.264 ;
      RECT 0.168 12.600 58.548 12.648 ;
      RECT 0.168 12.984 58.548 13.032 ;
      RECT 0.168 13.368 58.548 13.416 ;
      RECT 0.168 13.752 58.548 13.800 ;
      RECT 0.168 14.136 58.548 14.184 ;
      RECT 0.168 14.520 58.548 14.568 ;
      RECT 0.168 14.904 58.548 14.952 ;
      RECT 0.168 15.288 58.548 15.336 ;
      RECT 0.168 15.672 58.548 15.720 ;
      RECT 0.168 16.056 58.548 16.104 ;
      RECT 0.168 16.440 58.548 16.488 ;
      RECT 0.168 16.824 58.548 16.872 ;
      RECT 0.168 17.208 58.548 17.256 ;
      RECT 0.168 17.592 58.548 17.640 ;
      RECT 0.168 17.976 58.548 18.024 ;
      RECT 0.168 18.360 58.548 18.408 ;
      RECT 0.168 18.744 58.548 18.792 ;
      RECT 0.168 19.128 58.548 19.176 ;
      RECT 0.168 19.512 58.548 19.560 ;
      RECT 0.168 19.896 58.548 19.944 ;
      RECT 0.168 20.280 58.548 20.328 ;
      RECT 0.168 20.664 58.548 20.712 ;
      RECT 0.168 21.048 58.548 21.096 ;
      RECT 0.168 21.432 58.548 21.480 ;
      RECT 0.168 21.816 58.548 21.864 ;
      RECT 0.168 22.200 58.548 22.248 ;
      RECT 0.168 22.584 58.548 22.632 ;
      RECT 0.168 22.968 58.548 23.016 ;
      RECT 0.168 23.352 58.548 23.400 ;
      RECT 0.168 23.736 58.548 23.784 ;
      RECT 0.168 24.120 58.548 24.168 ;
      RECT 0.168 24.504 58.548 24.552 ;
      RECT 0.168 24.888 58.548 24.936 ;
      RECT 0.168 25.272 58.548 25.320 ;
      RECT 0.168 25.656 58.548 25.704 ;
      RECT 0.168 26.040 58.548 26.088 ;
      RECT 0.168 26.424 58.548 26.472 ;
      RECT 0.168 26.808 58.548 26.856 ;
      RECT 0.168 27.192 58.548 27.240 ;
      RECT 0.168 27.576 58.548 27.624 ;
      RECT 0.168 27.960 58.548 28.008 ;
      RECT 0.168 28.344 58.548 28.392 ;
      RECT 0.168 28.728 58.548 28.776 ;
      RECT 0.168 29.112 58.548 29.160 ;
      RECT 0.168 29.496 58.548 29.544 ;
      RECT 0.168 29.880 58.548 29.928 ;
      RECT 0.168 30.264 58.548 30.312 ;
      RECT 0.168 30.648 58.548 30.696 ;
      RECT 0.168 31.032 58.548 31.080 ;
      RECT 0.168 31.416 58.548 31.464 ;
      RECT 0.168 31.800 58.548 31.848 ;
      RECT 0.168 32.184 58.548 32.232 ;
      RECT 0.168 32.568 58.548 32.616 ;
      RECT 0.168 32.952 58.548 33.000 ;
      RECT 0.168 33.336 58.548 33.384 ;
      RECT 0.168 33.720 58.548 33.768 ;
      RECT 0.168 34.104 58.548 34.152 ;
      RECT 0.168 34.488 58.548 34.536 ;
      RECT 0.168 34.872 58.548 34.920 ;
      RECT 0.168 35.256 58.548 35.304 ;
      RECT 0.168 35.640 58.548 35.688 ;
      RECT 0.168 36.024 58.548 36.072 ;
      RECT 0.168 36.408 58.548 36.456 ;
    END
  END VDD
  OBS
    LAYER M1 ;
    RECT 0 0 58.716 36.720 ;
    LAYER M2 ;
    RECT 0 0 58.716 36.720 ;
    LAYER M3 ;
    RECT 0 0 58.716 36.720 ;
    LAYER M4 ;
    RECT 0 0 58.716 36.720 ;
  END
END fakeram7_256x64

END LIBRARY
